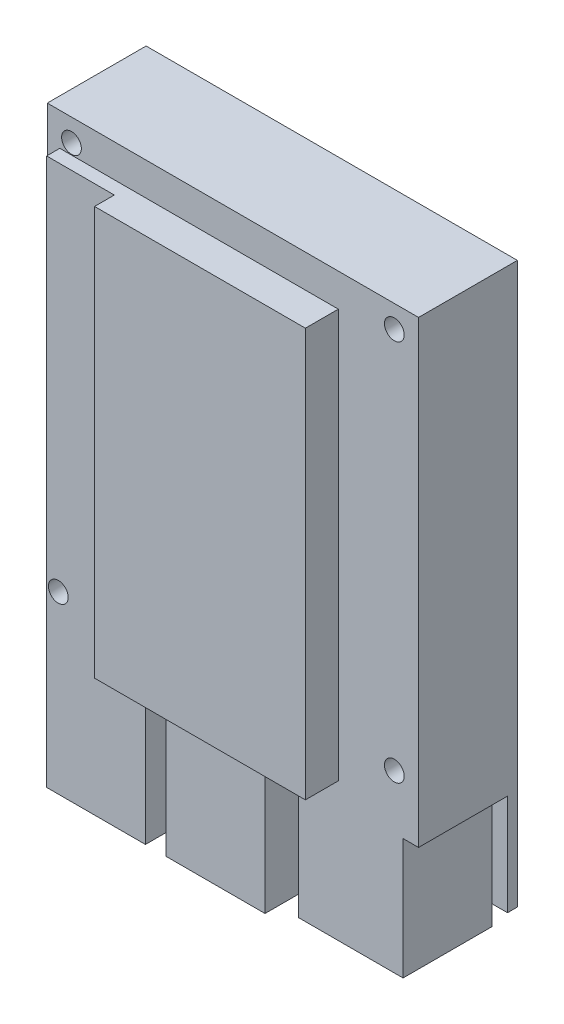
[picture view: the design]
ISO-10303-21;
HEADER;
FILE_DESCRIPTION(('STEP AP214'),'2;1');
FILE_NAME('part.step','',(''),(''),'','','');
FILE_SCHEMA(('AUTOMOTIVE_DESIGN { 1 0 10303 214 1 1 1 1 }'));
ENDSEC;
DATA;
#1=APPLICATION_CONTEXT('core data for automotive mechanical design processes');
#2=APPLICATION_PROTOCOL_DEFINITION('international standard','automotive_design',2000,#1);
#3=PRODUCT_CONTEXT('',#1,'mechanical');
#4=PRODUCT('Part','Part','',(#3));
#5=PRODUCT_RELATED_PRODUCT_CATEGORY('part','',(#4));
#6=PRODUCT_DEFINITION_FORMATION('','',#4);
#7=PRODUCT_DEFINITION_CONTEXT('part definition',#1,'design');
#8=PRODUCT_DEFINITION('design','',#6,#7);
#9=PRODUCT_DEFINITION_SHAPE('','',#8);
#10=(LENGTH_UNIT() NAMED_UNIT(*) SI_UNIT(.MILLI.,.METRE.));
#11=(NAMED_UNIT(*) PLANE_ANGLE_UNIT() SI_UNIT($,.RADIAN.));
#12=(NAMED_UNIT(*) SI_UNIT($,.STERADIAN.) SOLID_ANGLE_UNIT());
#13=UNCERTAINTY_MEASURE_WITH_UNIT(LENGTH_MEASURE(1.E-05),#10,'distance_accuracy_value','');
#14=(GEOMETRIC_REPRESENTATION_CONTEXT(3) GLOBAL_UNCERTAINTY_ASSIGNED_CONTEXT((#13)) GLOBAL_UNIT_ASSIGNED_CONTEXT((#10,
#11,#12)) REPRESENTATION_CONTEXT('',''));
#15=CARTESIAN_POINT('',(0.,0.,0.));
#16=DIRECTION('',(0.,0.,1.));
#17=DIRECTION('',(1.,0.,0.));
#18=AXIS2_PLACEMENT_3D('',#15,#16,#17);
#19=CARTESIAN_POINT('',(0.,85.,55.5));
#20=DIRECTION('',(0.,-1.,0.));
#21=DIRECTION('',(0.,0.,-1.));
#22=AXIS2_PLACEMENT_3D('',#19,#20,#21);
#23=PLANE('',#22);
#24=DIRECTION('',(0.,0.,-1.));
#25=VECTOR('',#24,1.);
#26=CARTESIAN_POINT('',(0.,85.,55.5));
#27=LINE('',#26,#25);
#28=CARTESIAN_POINT('',(0.,85.,50.5));
#29=VERTEX_POINT('',#28);
#30=CARTESIAN_POINT('',(0.,85.,35.5));
#31=VERTEX_POINT('',#30);
#32=EDGE_CURVE('E562',#29,#31,#27,.T.);
#33=ORIENTED_EDGE('',*,*,#32,.F.);
#34=DIRECTION('',(1.,0.,0.));
#35=VECTOR('',#34,1.);
#36=CARTESIAN_POINT('',(0.,85.,50.5));
#37=LINE('',#36,#35);
#38=CARTESIAN_POINT('',(56.35,85.,50.5));
#39=VERTEX_POINT('',#38);
#40=EDGE_CURVE('E549',#29,#39,#37,.T.);
#41=ORIENTED_EDGE('',*,*,#40,.T.);
#42=DIRECTION('',(0.,0.,-1.));
#43=VECTOR('',#42,1.);
#44=CARTESIAN_POINT('',(56.35,85.,55.5));
#45=LINE('',#44,#43);
#46=CARTESIAN_POINT('',(56.35,85.,35.5));
#47=VERTEX_POINT('',#46);
#48=EDGE_CURVE('E589',#39,#47,#45,.T.);
#49=ORIENTED_EDGE('',*,*,#48,.T.);
#50=DIRECTION('',(-1.,0.,0.));
#51=VECTOR('',#50,1.);
#52=CARTESIAN_POINT('',(-13.2262060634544,85.,35.5));
#53=LINE('',#52,#51);
#54=EDGE_CURVE('E374',#47,#31,#53,.T.);
#55=ORIENTED_EDGE('',*,*,#54,.T.);
#56=EDGE_LOOP('',(#33,#41,#49,#55));
#57=FACE_BOUND('',#56,.T.);
#58=ADVANCED_FACE('F58',(#57),#23,.F.);
#59=CARTESIAN_POINT('',(3.675,81.6,55.5));
#60=DIRECTION('',(0.,0.,-1.));
#61=DIRECTION('',(-1.,0.,0.));
#62=AXIS2_PLACEMENT_3D('',#59,#60,#61);
#63=CYLINDRICAL_SURFACE('',#62,1.5);
#64=CARTESIAN_POINT('',(3.675,81.6,35.5));
#65=DIRECTION('',(0.,0.,-1.));
#66=DIRECTION('',(-1.,0.,0.));
#67=AXIS2_PLACEMENT_3D('',#64,#65,#66);
#68=CIRCLE('',#67,1.5);
#69=CARTESIAN_POINT('',(2.175,81.6,35.5));
#70=VERTEX_POINT('',#69);
#71=EDGE_CURVE('E690',#70,#70,#68,.T.);
#72=ORIENTED_EDGE('',*,*,#71,.T.);
#73=EDGE_LOOP('',(#72));
#74=FACE_BOUND('',#73,.T.);
#75=CARTESIAN_POINT('',(3.675,81.6,50.5));
#76=DIRECTION('',(0.,0.,1.));
#77=DIRECTION('',(1.,0.,0.));
#78=AXIS2_PLACEMENT_3D('',#75,#76,#77);
#79=CIRCLE('',#78,1.5);
#80=CARTESIAN_POINT('',(5.175,81.6,50.5));
#81=VERTEX_POINT('',#80);
#82=EDGE_CURVE('E62',#81,#81,#79,.F.);
#83=ORIENTED_EDGE('',*,*,#82,.F.);
#84=EDGE_LOOP('',(#83));
#85=FACE_BOUND('',#84,.T.);
#86=ADVANCED_FACE('F803',(#74,#85),#63,.F.);
#87=CARTESIAN_POINT('',(0.,0.,55.5));
#88=DIRECTION('',(1.,0.,0.));
#89=DIRECTION('',(0.,0.,-1.));
#90=AXIS2_PLACEMENT_3D('',#87,#88,#89);
#91=PLANE('',#90);
#92=DIRECTION('',(0.,-1.,0.));
#93=VECTOR('',#92,1.);
#94=CARTESIAN_POINT('',(0.,85.,37.));
#95=LINE('',#94,#93);
#96=CARTESIAN_POINT('',(0.,15.3340933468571,37.));
#97=VERTEX_POINT('',#96);
#98=CARTESIAN_POINT('',(0.,0.,37.));
#99=VERTEX_POINT('',#98);
#100=EDGE_CURVE('E583',#97,#99,#95,.T.);
#101=ORIENTED_EDGE('',*,*,#100,.F.);
#102=DIRECTION('',(0.,0.,1.));
#103=VECTOR('',#102,1.);
#104=CARTESIAN_POINT('',(0.,15.3340933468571,-52.6027959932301));
#105=LINE('',#104,#103);
#106=CARTESIAN_POINT('',(0.,15.3340933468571,50.5));
#107=VERTEX_POINT('',#106);
#108=EDGE_CURVE('E660',#97,#107,#105,.T.);
#109=ORIENTED_EDGE('',*,*,#108,.T.);
#110=DIRECTION('',(0.,-1.,0.));
#111=VECTOR('',#110,1.);
#112=CARTESIAN_POINT('',(0.,85.,50.5));
#113=LINE('',#112,#111);
#114=EDGE_CURVE('E644',#29,#107,#113,.T.);
#115=ORIENTED_EDGE('',*,*,#114,.F.);
#116=ORIENTED_EDGE('',*,*,#32,.T.);
#117=DIRECTION('',(0.,-1.,0.));
#118=VECTOR('',#117,1.);
#119=CARTESIAN_POINT('',(0.,0.,35.5));
#120=LINE('',#119,#118);
#121=CARTESIAN_POINT('',(0.,0.,35.5));
#122=VERTEX_POINT('',#121);
#123=EDGE_CURVE('E384',#31,#122,#120,.T.);
#124=ORIENTED_EDGE('',*,*,#123,.T.);
#125=DIRECTION('',(0.,0.,-1.));
#126=VECTOR('',#125,1.);
#127=CARTESIAN_POINT('',(0.,0.,55.5));
#128=LINE('',#127,#126);
#129=EDGE_CURVE('E597',#99,#122,#128,.T.);
#130=ORIENTED_EDGE('',*,*,#129,.F.);
#131=EDGE_LOOP('',(#101,#109,#115,#116,#124,#130));
#132=FACE_BOUND('',#131,.T.);
#133=DIRECTION('',(0.,0.,1.));
#134=VECTOR('',#133,1.);
#135=CARTESIAN_POINT('',(0.,27.2,37.));
#136=LINE('',#135,#134);
#137=CARTESIAN_POINT('',(0.,27.2,37.));
#138=VERTEX_POINT('',#137);
#139=CARTESIAN_POINT('',(0.,27.2,43.5));
#140=VERTEX_POINT('',#139);
#141=EDGE_CURVE('E668',#138,#140,#136,.T.);
#142=ORIENTED_EDGE('',*,*,#141,.F.);
#143=CARTESIAN_POINT('',(0.,79.7,37.));
#144=VERTEX_POINT('',#143);
#145=EDGE_CURVE('E582',#144,#138,#95,.T.);
#146=ORIENTED_EDGE('',*,*,#145,.F.);
#147=DIRECTION('',(0.,0.,-1.));
#148=VECTOR('',#147,1.);
#149=CARTESIAN_POINT('',(0.,79.7,37.));
#150=LINE('',#149,#148);
#151=CARTESIAN_POINT('',(0.,79.7,43.5));
#152=VERTEX_POINT('',#151);
#153=EDGE_CURVE('E600',#152,#144,#150,.T.);
#154=ORIENTED_EDGE('',*,*,#153,.F.);
#155=DIRECTION('',(0.,1.,0.));
#156=VECTOR('',#155,1.);
#157=CARTESIAN_POINT('',(0.,79.7,43.5));
#158=LINE('',#157,#156);
#159=EDGE_CURVE('E664',#140,#152,#158,.T.);
#160=ORIENTED_EDGE('',*,*,#159,.F.);
#161=EDGE_LOOP('',(#142,#146,#154,#160));
#162=FACE_BOUND('',#161,.T.);
#163=ADVANCED_FACE('F60',(#132,#162),#91,.F.);
#164=CARTESIAN_POINT('',(1.90000000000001,85.,0.));
#165=DIRECTION('',(-1.,0.,0.));
#166=DIRECTION('',(0.,0.,1.));
#167=AXIS2_PLACEMENT_3D('',#164,#165,#166);
#168=PLANE('',#167);
#169=DIRECTION('',(0.,0.,1.));
#170=VECTOR('',#169,1.);
#171=CARTESIAN_POINT('',(1.90000000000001,80.,0.));
#172=LINE('',#171,#170);
#173=CARTESIAN_POINT('',(1.90000000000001,80.,50.5));
#174=VERTEX_POINT('',#173);
#175=CARTESIAN_POINT('',(1.90000000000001,80.,52.5));
#176=VERTEX_POINT('',#175);
#177=EDGE_CURVE('E77',#174,#176,#172,.T.);
#178=ORIENTED_EDGE('',*,*,#177,.F.);
#179=DIRECTION('',(0.,1.,0.));
#180=VECTOR('',#179,1.);
#181=CARTESIAN_POINT('',(1.90000000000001,85.,50.5));
#182=LINE('',#181,#180);
#183=CARTESIAN_POINT('',(1.90000000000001,15.3340933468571,50.5));
#184=VERTEX_POINT('',#183);
#185=EDGE_CURVE('E334',#184,#174,#182,.T.);
#186=ORIENTED_EDGE('',*,*,#185,.F.);
#187=DIRECTION('',(0.,0.,1.));
#188=VECTOR('',#187,1.);
#189=CARTESIAN_POINT('',(1.90000000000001,15.3340933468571,0.));
#190=LINE('',#189,#188);
#191=CARTESIAN_POINT('',(1.90000000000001,15.3340933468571,37.));
#192=VERTEX_POINT('',#191);
#193=EDGE_CURVE('E370',#192,#184,#190,.T.);
#194=ORIENTED_EDGE('',*,*,#193,.F.);
#195=DIRECTION('',(0.,-1.,0.));
#196=VECTOR('',#195,1.);
#197=CARTESIAN_POINT('',(1.90000000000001,85.,37.));
#198=LINE('',#197,#196);
#199=CARTESIAN_POINT('',(1.90000000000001,0.,37.));
#200=VERTEX_POINT('',#199);
#201=EDGE_CURVE('E580',#192,#200,#198,.T.);
#202=ORIENTED_EDGE('',*,*,#201,.T.);
#203=DIRECTION('',(0.,1.,0.));
#204=VECTOR('',#203,1.);
#205=CARTESIAN_POINT('',(1.90000000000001,-3.,37.));
#206=LINE('',#205,#204);
#207=CARTESIAN_POINT('',(1.90000000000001,-3.,37.));
#208=VERTEX_POINT('',#207);
#209=EDGE_CURVE('E427',#208,#200,#206,.T.);
#210=ORIENTED_EDGE('',*,*,#209,.F.);
#211=DIRECTION('',(0.,0.,-1.));
#212=VECTOR('',#211,1.);
#213=CARTESIAN_POINT('',(1.90000000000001,-3.,0.));
#214=LINE('',#213,#212);
#215=CARTESIAN_POINT('',(1.90000000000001,-3.,52.5));
#216=VERTEX_POINT('',#215);
#217=EDGE_CURVE('E424',#216,#208,#214,.T.);
#218=ORIENTED_EDGE('',*,*,#217,.F.);
#219=DIRECTION('',(0.,-1.,0.));
#220=VECTOR('',#219,1.);
#221=CARTESIAN_POINT('',(1.90000000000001,85.,52.5));
#222=LINE('',#221,#220);
#223=EDGE_CURVE('E336',#176,#216,#222,.T.);
#224=ORIENTED_EDGE('',*,*,#223,.F.);
#225=EDGE_LOOP('',(#178,#186,#194,#202,#210,#218,#224));
#226=FACE_BOUND('',#225,.T.);
#227=ADVANCED_FACE('F332',(#226),#168,.T.);
#228=CARTESIAN_POINT('',(0.,85.,37.));
#229=DIRECTION('',(0.,0.,-1.));
#230=DIRECTION('',(-1.,0.,0.));
#231=AXIS2_PLACEMENT_3D('',#228,#229,#230);
#232=PLANE('',#231);
#233=ORIENTED_EDGE('',*,*,#201,.F.);
#234=DIRECTION('',(1.,0.,0.));
#235=VECTOR('',#234,1.);
#236=CARTESIAN_POINT('',(0.,15.3340933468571,37.));
#237=LINE('',#236,#235);
#238=EDGE_CURVE('E652',#97,#192,#237,.T.);
#239=ORIENTED_EDGE('',*,*,#238,.F.);
#240=ORIENTED_EDGE('',*,*,#100,.T.);
#241=DIRECTION('',(1.,0.,0.));
#242=VECTOR('',#241,1.);
#243=CARTESIAN_POINT('',(0.,0.,37.));
#244=LINE('',#243,#242);
#245=EDGE_CURVE('E529',#99,#200,#244,.T.);
#246=ORIENTED_EDGE('',*,*,#245,.T.);
#247=EDGE_LOOP('',(#233,#239,#240,#246));
#248=FACE_BOUND('',#247,.T.);
#249=ADVANCED_FACE('F782',(#248),#232,.F.);
#250=CARTESIAN_POINT('',(0.,0.,55.5));
#251=DIRECTION('',(0.,1.,0.));
#252=DIRECTION('',(0.,0.,1.));
#253=AXIS2_PLACEMENT_3D('',#250,#251,#252);
#254=PLANE('',#253);
#255=ORIENTED_EDGE('',*,*,#129,.T.);
#256=DIRECTION('',(-1.,0.,0.));
#257=VECTOR('',#256,1.);
#258=CARTESIAN_POINT('',(-13.2262060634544,0.,35.5));
#259=LINE('',#258,#257);
#260=CARTESIAN_POINT('',(56.35,0.,35.5));
#261=VERTEX_POINT('',#260);
#262=EDGE_CURVE('E373',#261,#122,#259,.T.);
#263=ORIENTED_EDGE('',*,*,#262,.F.);
#264=DIRECTION('',(0.,0.,-1.));
#265=VECTOR('',#264,1.);
#266=CARTESIAN_POINT('',(56.35,0.,55.5));
#267=LINE('',#266,#265);
#268=CARTESIAN_POINT('',(56.35,0.,37.));
#269=VERTEX_POINT('',#268);
#270=EDGE_CURVE('E593',#269,#261,#267,.T.);
#271=ORIENTED_EDGE('',*,*,#270,.F.);
#272=DIRECTION('',(1.,0.,0.));
#273=VECTOR('',#272,1.);
#274=CARTESIAN_POINT('',(0.,0.,37.));
#275=LINE('',#274,#273);
#276=CARTESIAN_POINT('',(54.,0.,37.));
#277=VERTEX_POINT('',#276);
#278=EDGE_CURVE('E554',#277,#269,#275,.T.);
#279=ORIENTED_EDGE('',*,*,#278,.F.);
#280=DIRECTION('',(1.,0.,0.));
#281=VECTOR('',#280,1.);
#282=CARTESIAN_POINT('',(0.,0.,37.));
#283=LINE('',#282,#281);
#284=CARTESIAN_POINT('',(38.1,0.,37.));
#285=VERTEX_POINT('',#284);
#286=EDGE_CURVE('E412',#285,#277,#283,.T.);
#287=ORIENTED_EDGE('',*,*,#286,.F.);
#288=DIRECTION('',(1.,0.,0.));
#289=VECTOR('',#288,1.);
#290=CARTESIAN_POINT('',(0.,0.,37.));
#291=LINE('',#290,#289);
#292=CARTESIAN_POINT('',(35.05,0.,37.));
#293=VERTEX_POINT('',#292);
#294=EDGE_CURVE('E492',#293,#285,#291,.T.);
#295=ORIENTED_EDGE('',*,*,#294,.F.);
#296=DIRECTION('',(1.,0.,0.));
#297=VECTOR('',#296,1.);
#298=CARTESIAN_POINT('',(0.,0.,37.));
#299=LINE('',#298,#297);
#300=CARTESIAN_POINT('',(20.05,0.,37.));
#301=VERTEX_POINT('',#300);
#302=EDGE_CURVE('E442',#301,#293,#299,.T.);
#303=ORIENTED_EDGE('',*,*,#302,.F.);
#304=CARTESIAN_POINT('',(16.9,0.,37.));
#305=VERTEX_POINT('',#304);
#306=EDGE_CURVE('E436',#305,#301,#291,.T.);
#307=ORIENTED_EDGE('',*,*,#306,.F.);
#308=DIRECTION('',(1.,0.,0.));
#309=VECTOR('',#308,1.);
#310=CARTESIAN_POINT('',(0.,0.,37.));
#311=LINE('',#310,#309);
#312=EDGE_CURVE('E416',#200,#305,#311,.T.);
#313=ORIENTED_EDGE('',*,*,#312,.F.);
#314=ORIENTED_EDGE('',*,*,#245,.F.);
#315=EDGE_LOOP('',(#255,#263,#271,#279,#287,#295,#303,#307,#313,#314));
#316=FACE_BOUND('',#315,.T.);
#317=ADVANCED_FACE('F755',(#316),#254,.F.);
#318=CARTESIAN_POINT('',(0.,0.,55.5));
#319=DIRECTION('',(0.,0.,-1.));
#320=DIRECTION('',(-1.,0.,0.));
#321=AXIS2_PLACEMENT_3D('',#318,#319,#320);
#322=PLANE('',#321);
#323=DIRECTION('',(0.,-1.,0.));
#324=VECTOR('',#323,1.);
#325=CARTESIAN_POINT('',(44.175,85.,55.5));
#326=LINE('',#325,#324);
#327=CARTESIAN_POINT('',(44.175,80.,55.5));
#328=VERTEX_POINT('',#327);
#329=CARTESIAN_POINT('',(44.175,18.,55.5));
#330=VERTEX_POINT('',#329);
#331=EDGE_CURVE('E553',#328,#330,#326,.T.);
#332=ORIENTED_EDGE('',*,*,#331,.F.);
#333=DIRECTION('',(1.,0.,0.));
#334=VECTOR('',#333,1.);
#335=CARTESIAN_POINT('',(-13.2086276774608,80.,55.5));
#336=LINE('',#335,#334);
#337=CARTESIAN_POINT('',(12.175,80.,55.5));
#338=VERTEX_POINT('',#337);
#339=EDGE_CURVE('E327',#338,#328,#336,.T.);
#340=ORIENTED_EDGE('',*,*,#339,.F.);
#341=DIRECTION('',(0.,-1.,0.));
#342=VECTOR('',#341,1.);
#343=CARTESIAN_POINT('',(12.175,85.,55.5));
#344=LINE('',#343,#342);
#345=CARTESIAN_POINT('',(12.175,18.,55.5));
#346=VERTEX_POINT('',#345);
#347=EDGE_CURVE('E576',#338,#346,#344,.T.);
#348=ORIENTED_EDGE('',*,*,#347,.T.);
#349=DIRECTION('',(-1.,0.,0.));
#350=VECTOR('',#349,1.);
#351=CARTESIAN_POINT('',(0.,18.,55.5));
#352=LINE('',#351,#350);
#353=EDGE_CURVE('E491',#330,#346,#352,.T.);
#354=ORIENTED_EDGE('',*,*,#353,.F.);
#355=EDGE_LOOP('',(#332,#340,#348,#354));
#356=FACE_BOUND('',#355,.T.);
#357=ADVANCED_FACE('F717',(#356),#322,.F.);
#358=CARTESIAN_POINT('',(44.175,85.,0.));
#359=DIRECTION('',(-1.,0.,0.));
#360=DIRECTION('',(0.,0.,1.));
#361=AXIS2_PLACEMENT_3D('',#358,#359,#360);
#362=PLANE('',#361);
#363=DIRECTION('',(0.,-1.,0.));
#364=VECTOR('',#363,1.);
#365=CARTESIAN_POINT('',(44.175,85.,50.5));
#366=LINE('',#365,#364);
#367=CARTESIAN_POINT('',(44.175,80.,50.5));
#368=VERTEX_POINT('',#367);
#369=CARTESIAN_POINT('',(44.175,18.,50.5));
#370=VERTEX_POINT('',#369);
#371=EDGE_CURVE('E569',#368,#370,#366,.T.);
#372=ORIENTED_EDGE('',*,*,#371,.F.);
#373=DIRECTION('',(0.,0.,1.));
#374=VECTOR('',#373,1.);
#375=CARTESIAN_POINT('',(44.175,80.,0.));
#376=LINE('',#375,#374);
#377=EDGE_CURVE('E322',#368,#328,#376,.T.);
#378=ORIENTED_EDGE('',*,*,#377,.T.);
#379=ORIENTED_EDGE('',*,*,#331,.T.);
#380=DIRECTION('',(0.,0.,-1.));
#381=VECTOR('',#380,1.);
#382=CARTESIAN_POINT('',(44.175,18.,0.));
#383=LINE('',#382,#381);
#384=EDGE_CURVE('E487',#330,#370,#383,.T.);
#385=ORIENTED_EDGE('',*,*,#384,.T.);
#386=EDGE_LOOP('',(#372,#378,#379,#385));
#387=FACE_BOUND('',#386,.T.);
#388=ADVANCED_FACE('F715',(#387),#362,.F.);
#389=CARTESIAN_POINT('',(12.175,85.,0.));
#390=DIRECTION('',(-1.,0.,0.));
#391=DIRECTION('',(0.,0.,1.));
#392=AXIS2_PLACEMENT_3D('',#389,#390,#391);
#393=PLANE('',#392);
#394=DIRECTION('',(0.,0.,1.));
#395=VECTOR('',#394,1.);
#396=CARTESIAN_POINT('',(12.175,80.,0.));
#397=LINE('',#396,#395);
#398=CARTESIAN_POINT('',(12.175,80.,52.5));
#399=VERTEX_POINT('',#398);
#400=EDGE_CURVE('E338',#399,#338,#397,.T.);
#401=ORIENTED_EDGE('',*,*,#400,.F.);
#402=DIRECTION('',(0.,-1.,0.));
#403=VECTOR('',#402,1.);
#404=CARTESIAN_POINT('',(12.175,85.,52.5));
#405=LINE('',#404,#403);
#406=CARTESIAN_POINT('',(12.175,18.,52.5));
#407=VERTEX_POINT('',#406);
#408=EDGE_CURVE('E558',#399,#407,#405,.T.);
#409=ORIENTED_EDGE('',*,*,#408,.T.);
#410=DIRECTION('',(0.,0.,-1.));
#411=VECTOR('',#410,1.);
#412=CARTESIAN_POINT('',(12.175,18.,0.));
#413=LINE('',#412,#411);
#414=EDGE_CURVE('E496',#346,#407,#413,.T.);
#415=ORIENTED_EDGE('',*,*,#414,.F.);
#416=ORIENTED_EDGE('',*,*,#347,.F.);
#417=EDGE_LOOP('',(#401,#409,#415,#416));
#418=FACE_BOUND('',#417,.T.);
#419=ADVANCED_FACE('F721',(#418),#393,.T.);
#420=CARTESIAN_POINT('',(56.35,0.,55.5));
#421=DIRECTION('',(-1.,0.,0.));
#422=DIRECTION('',(0.,0.,1.));
#423=AXIS2_PLACEMENT_3D('',#420,#421,#422);
#424=PLANE('',#423);
#425=ORIENTED_EDGE('',*,*,#270,.T.);
#426=DIRECTION('',(0.,1.,0.));
#427=VECTOR('',#426,1.);
#428=CARTESIAN_POINT('',(56.35,0.,35.5));
#429=LINE('',#428,#427);
#430=EDGE_CURVE('E378',#261,#47,#429,.T.);
#431=ORIENTED_EDGE('',*,*,#430,.T.);
#432=ORIENTED_EDGE('',*,*,#48,.F.);
#433=DIRECTION('',(0.,1.,0.));
#434=VECTOR('',#433,1.);
#435=CARTESIAN_POINT('',(56.35,85.,50.5));
#436=LINE('',#435,#434);
#437=CARTESIAN_POINT('',(56.35,15.3340933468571,50.5));
#438=VERTEX_POINT('',#437);
#439=EDGE_CURVE('E647',#438,#39,#436,.T.);
#440=ORIENTED_EDGE('',*,*,#439,.F.);
#441=DIRECTION('',(0.,0.,1.));
#442=VECTOR('',#441,1.);
#443=CARTESIAN_POINT('',(56.35,15.3340933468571,-52.6027959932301));
#444=LINE('',#443,#442);
#445=CARTESIAN_POINT('',(56.35,15.3340933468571,37.));
#446=VERTEX_POINT('',#445);
#447=EDGE_CURVE('E654',#446,#438,#444,.T.);
#448=ORIENTED_EDGE('',*,*,#447,.F.);
#449=DIRECTION('',(0.,-1.,0.));
#450=VECTOR('',#449,1.);
#451=CARTESIAN_POINT('',(56.35,85.,37.));
#452=LINE('',#451,#450);
#453=EDGE_CURVE('E559',#446,#269,#452,.T.);
#454=ORIENTED_EDGE('',*,*,#453,.T.);
#455=EDGE_LOOP('',(#425,#431,#432,#440,#448,#454));
#456=FACE_BOUND('',#455,.T.);
#457=ADVANCED_FACE('F769',(#456),#424,.F.);
#458=CARTESIAN_POINT('',(0.,85.,37.));
#459=DIRECTION('',(0.,0.,-1.));
#460=DIRECTION('',(-1.,0.,0.));
#461=AXIS2_PLACEMENT_3D('',#458,#459,#460);
#462=PLANE('',#461);
#463=ORIENTED_EDGE('',*,*,#453,.F.);
#464=CARTESIAN_POINT('',(54.,15.3340933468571,37.));
#465=VERTEX_POINT('',#464);
#466=EDGE_CURVE('E656',#465,#446,#237,.T.);
#467=ORIENTED_EDGE('',*,*,#466,.F.);
#468=DIRECTION('',(0.,-1.,0.));
#469=VECTOR('',#468,1.);
#470=CARTESIAN_POINT('',(54.,85.,37.));
#471=LINE('',#470,#469);
#472=EDGE_CURVE('E563',#465,#277,#471,.T.);
#473=ORIENTED_EDGE('',*,*,#472,.T.);
#474=ORIENTED_EDGE('',*,*,#278,.T.);
#475=EDGE_LOOP('',(#463,#467,#473,#474));
#476=FACE_BOUND('',#475,.T.);
#477=ADVANCED_FACE('F814',(#476),#462,.F.);
#478=CARTESIAN_POINT('',(54.,85.,0.));
#479=DIRECTION('',(-1.,0.,0.));
#480=DIRECTION('',(0.,0.,1.));
#481=AXIS2_PLACEMENT_3D('',#478,#479,#480);
#482=PLANE('',#481);
#483=ORIENTED_EDGE('',*,*,#472,.F.);
#484=DIRECTION('',(0.,0.,1.));
#485=VECTOR('',#484,1.);
#486=CARTESIAN_POINT('',(54.,15.3340933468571,0.));
#487=LINE('',#486,#485);
#488=CARTESIAN_POINT('',(54.,15.3340933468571,50.5));
#489=VERTEX_POINT('',#488);
#490=EDGE_CURVE('E366',#465,#489,#487,.T.);
#491=ORIENTED_EDGE('',*,*,#490,.T.);
#492=DIRECTION('',(0.,-1.,0.));
#493=VECTOR('',#492,1.);
#494=CARTESIAN_POINT('',(54.,85.,50.5));
#495=LINE('',#494,#493);
#496=CARTESIAN_POINT('',(54.,-3.,50.5));
#497=VERTEX_POINT('',#496);
#498=EDGE_CURVE('E566',#489,#497,#495,.T.);
#499=ORIENTED_EDGE('',*,*,#498,.T.);
#500=DIRECTION('',(0.,0.,-1.));
#501=VECTOR('',#500,1.);
#502=CARTESIAN_POINT('',(54.,-3.,0.));
#503=LINE('',#502,#501);
#504=CARTESIAN_POINT('',(54.,-3.,37.));
#505=VERTEX_POINT('',#504);
#506=EDGE_CURVE('E466',#497,#505,#503,.T.);
#507=ORIENTED_EDGE('',*,*,#506,.T.);
#508=DIRECTION('',(0.,1.,0.));
#509=VECTOR('',#508,1.);
#510=CARTESIAN_POINT('',(54.,-3.,37.));
#511=LINE('',#510,#509);
#512=EDGE_CURVE('E456',#505,#277,#511,.T.);
#513=ORIENTED_EDGE('',*,*,#512,.T.);
#514=EDGE_LOOP('',(#483,#491,#499,#507,#513));
#515=FACE_BOUND('',#514,.T.);
#516=ADVANCED_FACE('F845',(#515),#482,.F.);
#517=CARTESIAN_POINT('',(0.,85.,50.5));
#518=DIRECTION('',(0.,0.,-1.));
#519=DIRECTION('',(-1.,0.,0.));
#520=AXIS2_PLACEMENT_3D('',#517,#518,#519);
#521=PLANE('',#520);
#522=CARTESIAN_POINT('',(52.675,23.6,50.5));
#523=DIRECTION('',(0.,0.,-1.));
#524=DIRECTION('',(-1.,0.,0.));
#525=AXIS2_PLACEMENT_3D('',#522,#523,#524);
#526=CIRCLE('',#525,1.5);
#527=CARTESIAN_POINT('',(51.175,23.6,50.5));
#528=VERTEX_POINT('',#527);
#529=EDGE_CURVE('E651',#528,#528,#526,.T.);
#530=ORIENTED_EDGE('',*,*,#529,.T.);
#531=EDGE_LOOP('',(#530));
#532=FACE_BOUND('',#531,.T.);
#533=ORIENTED_EDGE('',*,*,#439,.T.);
#534=ORIENTED_EDGE('',*,*,#40,.F.);
#535=ORIENTED_EDGE('',*,*,#114,.T.);
#536=DIRECTION('',(1.,0.,0.));
#537=VECTOR('',#536,1.);
#538=CARTESIAN_POINT('',(0.,15.3340933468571,50.5));
#539=LINE('',#538,#537);
#540=EDGE_CURVE('E344',#107,#184,#539,.T.);
#541=ORIENTED_EDGE('',*,*,#540,.T.);
#542=ORIENTED_EDGE('',*,*,#185,.T.);
#543=DIRECTION('',(1.,0.,0.));
#544=VECTOR('',#543,1.);
#545=CARTESIAN_POINT('',(-13.2086276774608,80.,50.5));
#546=LINE('',#545,#544);
#547=EDGE_CURVE('E319',#174,#368,#546,.T.);
#548=ORIENTED_EDGE('',*,*,#547,.T.);
#549=ORIENTED_EDGE('',*,*,#371,.T.);
#550=DIRECTION('',(1.,0.,0.));
#551=VECTOR('',#550,1.);
#552=CARTESIAN_POINT('',(0.,18.,50.5));
#553=LINE('',#552,#551);
#554=CARTESIAN_POINT('',(35.05,18.,50.5));
#555=VERTEX_POINT('',#554);
#556=EDGE_CURVE('E519',#555,#370,#553,.T.);
#557=ORIENTED_EDGE('',*,*,#556,.F.);
#558=DIRECTION('',(0.,1.,0.));
#559=VECTOR('',#558,1.);
#560=CARTESIAN_POINT('',(35.05,18.,50.5));
#561=LINE('',#560,#559);
#562=CARTESIAN_POINT('',(35.05,15.3340933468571,50.5));
#563=VERTEX_POINT('',#562);
#564=EDGE_CURVE('E347',#563,#555,#561,.T.);
#565=ORIENTED_EDGE('',*,*,#564,.F.);
#566=CARTESIAN_POINT('',(38.1,15.3340933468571,50.5));
#567=VERTEX_POINT('',#566);
#568=EDGE_CURVE('E634',#563,#567,#539,.T.);
#569=ORIENTED_EDGE('',*,*,#568,.T.);
#570=DIRECTION('',(0.,-1.,0.));
#571=VECTOR('',#570,1.);
#572=CARTESIAN_POINT('',(38.1,18.,50.5));
#573=LINE('',#572,#571);
#574=CARTESIAN_POINT('',(38.1,-3.,50.5));
#575=VERTEX_POINT('',#574);
#576=EDGE_CURVE('E88',#567,#575,#573,.T.);
#577=ORIENTED_EDGE('',*,*,#576,.T.);
#578=DIRECTION('',(1.,0.,0.));
#579=VECTOR('',#578,1.);
#580=CARTESIAN_POINT('',(0.,-3.,50.5));
#581=LINE('',#580,#579);
#582=EDGE_CURVE('E470',#575,#497,#581,.T.);
#583=ORIENTED_EDGE('',*,*,#582,.T.);
#584=ORIENTED_EDGE('',*,*,#498,.F.);
#585=EDGE_CURVE('E640',#489,#438,#539,.T.);
#586=ORIENTED_EDGE('',*,*,#585,.T.);
#587=EDGE_LOOP('',(#533,#534,#535,#541,#542,#548,#549,#557,#565,#569,#577,#583,#584,#586));
#588=FACE_BOUND('',#587,.T.);
#589=CARTESIAN_POINT('',(52.675,81.6,50.5));
#590=DIRECTION('',(0.,0.,-1.));
#591=DIRECTION('',(-1.,0.,0.));
#592=AXIS2_PLACEMENT_3D('',#589,#590,#591);
#593=CIRCLE('',#592,1.5);
#594=CARTESIAN_POINT('',(51.175,81.6,50.5));
#595=VERTEX_POINT('',#594);
#596=EDGE_CURVE('E676',#595,#595,#593,.T.);
#597=ORIENTED_EDGE('',*,*,#596,.T.);
#598=EDGE_LOOP('',(#597));
#599=FACE_BOUND('',#598,.T.);
#600=ORIENTED_EDGE('',*,*,#82,.T.);
#601=EDGE_LOOP('',(#600));
#602=FACE_BOUND('',#601,.T.);
#603=ADVANCED_FACE('F341',(#532,#588,#599,#602),#521,.F.);
#604=CARTESIAN_POINT('',(0.,85.,52.5));
#605=DIRECTION('',(0.,0.,-1.));
#606=DIRECTION('',(-1.,0.,0.));
#607=AXIS2_PLACEMENT_3D('',#604,#605,#606);
#608=PLANE('',#607);
#609=CARTESIAN_POINT('',(3.67500000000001,23.6,52.5));
#610=DIRECTION('',(0.,0.,-1.));
#611=DIRECTION('',(-1.,0.,0.));
#612=AXIS2_PLACEMENT_3D('',#609,#610,#611);
#613=CIRCLE('',#612,1.5);
#614=CARTESIAN_POINT('',(2.17500000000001,23.6,52.5));
#615=VERTEX_POINT('',#614);
#616=EDGE_CURVE('E674',#615,#615,#613,.T.);
#617=ORIENTED_EDGE('',*,*,#616,.T.);
#618=EDGE_LOOP('',(#617));
#619=FACE_BOUND('',#618,.T.);
#620=ORIENTED_EDGE('',*,*,#408,.F.);
#621=DIRECTION('',(-1.,0.,0.));
#622=VECTOR('',#621,1.);
#623=CARTESIAN_POINT('',(0.,80.,52.5));
#624=LINE('',#623,#622);
#625=EDGE_CURVE('E704',#399,#176,#624,.T.);
#626=ORIENTED_EDGE('',*,*,#625,.T.);
#627=ORIENTED_EDGE('',*,*,#223,.T.);
#628=DIRECTION('',(1.,0.,0.));
#629=VECTOR('',#628,1.);
#630=CARTESIAN_POINT('',(0.,-3.,52.5));
#631=LINE('',#630,#629);
#632=CARTESIAN_POINT('',(16.9,-3.,52.5));
#633=VERTEX_POINT('',#632);
#634=EDGE_CURVE('E420',#216,#633,#631,.T.);
#635=ORIENTED_EDGE('',*,*,#634,.T.);
#636=DIRECTION('',(0.,-1.,0.));
#637=VECTOR('',#636,1.);
#638=CARTESIAN_POINT('',(16.9,18.,52.5));
#639=LINE('',#638,#637);
#640=CARTESIAN_POINT('',(16.9,18.,52.5));
#641=VERTEX_POINT('',#640);
#642=EDGE_CURVE('E523',#641,#633,#639,.T.);
#643=ORIENTED_EDGE('',*,*,#642,.F.);
#644=DIRECTION('',(1.,0.,0.));
#645=VECTOR('',#644,1.);
#646=CARTESIAN_POINT('',(0.,18.,52.5));
#647=LINE('',#646,#645);
#648=EDGE_CURVE('E500',#407,#641,#647,.T.);
#649=ORIENTED_EDGE('',*,*,#648,.F.);
#650=EDGE_LOOP('',(#620,#626,#627,#635,#643,#649));
#651=FACE_BOUND('',#650,.T.);
#652=ADVANCED_FACE('F724',(#619,#651),#608,.F.);
#653=CARTESIAN_POINT('',(38.1,18.,0.));
#654=DIRECTION('',(-1.,0.,0.));
#655=DIRECTION('',(0.,0.,1.));
#656=AXIS2_PLACEMENT_3D('',#653,#654,#655);
#657=PLANE('',#656);
#658=DIRECTION('',(0.,0.,1.));
#659=VECTOR('',#658,1.);
#660=CARTESIAN_POINT('',(38.1,15.3340933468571,0.));
#661=LINE('',#660,#659);
#662=CARTESIAN_POINT('',(38.1,15.3340933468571,37.));
#663=VERTEX_POINT('',#662);
#664=EDGE_CURVE('E363',#663,#567,#661,.T.);
#665=ORIENTED_EDGE('',*,*,#664,.F.);
#666=DIRECTION('',(0.,-1.,0.));
#667=VECTOR('',#666,1.);
#668=CARTESIAN_POINT('',(38.1,18.,37.));
#669=LINE('',#668,#667);
#670=EDGE_CURVE('E530',#663,#285,#669,.T.);
#671=ORIENTED_EDGE('',*,*,#670,.T.);
#672=DIRECTION('',(0.,1.,0.));
#673=VECTOR('',#672,1.);
#674=CARTESIAN_POINT('',(38.1,-3.,37.));
#675=LINE('',#674,#673);
#676=CARTESIAN_POINT('',(38.1,-3.,37.));
#677=VERTEX_POINT('',#676);
#678=EDGE_CURVE('E477',#677,#285,#675,.T.);
#679=ORIENTED_EDGE('',*,*,#678,.F.);
#680=DIRECTION('',(0.,0.,-1.));
#681=VECTOR('',#680,1.);
#682=CARTESIAN_POINT('',(38.1,-3.,0.));
#683=LINE('',#682,#681);
#684=EDGE_CURVE('E474',#575,#677,#683,.T.);
#685=ORIENTED_EDGE('',*,*,#684,.F.);
#686=ORIENTED_EDGE('',*,*,#576,.F.);
#687=EDGE_LOOP('',(#665,#671,#679,#685,#686));
#688=FACE_BOUND('',#687,.T.);
#689=ADVANCED_FACE('F839',(#688),#657,.T.);
#690=CARTESIAN_POINT('',(0.,18.,37.));
#691=DIRECTION('',(0.,0.,-1.));
#692=DIRECTION('',(-1.,0.,0.));
#693=AXIS2_PLACEMENT_3D('',#690,#691,#692);
#694=PLANE('',#693);
#695=ORIENTED_EDGE('',*,*,#670,.F.);
#696=CARTESIAN_POINT('',(35.05,15.3340933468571,37.));
#697=VERTEX_POINT('',#696);
#698=EDGE_CURVE('E753',#697,#663,#237,.T.);
#699=ORIENTED_EDGE('',*,*,#698,.F.);
#700=DIRECTION('',(0.,-1.,0.));
#701=VECTOR('',#700,1.);
#702=CARTESIAN_POINT('',(35.05,18.,37.));
#703=LINE('',#702,#701);
#704=EDGE_CURVE('E533',#697,#293,#703,.T.);
#705=ORIENTED_EDGE('',*,*,#704,.T.);
#706=ORIENTED_EDGE('',*,*,#294,.T.);
#707=EDGE_LOOP('',(#695,#699,#705,#706));
#708=FACE_BOUND('',#707,.T.);
#709=ADVANCED_FACE('F752',(#708),#694,.F.);
#710=CARTESIAN_POINT('',(35.05,18.,0.));
#711=DIRECTION('',(-1.,0.,0.));
#712=DIRECTION('',(0.,0.,1.));
#713=AXIS2_PLACEMENT_3D('',#710,#711,#712);
#714=PLANE('',#713);
#715=DIRECTION('',(0.,0.,1.));
#716=VECTOR('',#715,1.);
#717=CARTESIAN_POINT('',(35.05,15.3340933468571,0.));
#718=LINE('',#717,#716);
#719=EDGE_CURVE('E353',#697,#563,#718,.T.);
#720=ORIENTED_EDGE('',*,*,#719,.T.);
#721=ORIENTED_EDGE('',*,*,#564,.T.);
#722=DIRECTION('',(0.,0.,-1.));
#723=VECTOR('',#722,1.);
#724=CARTESIAN_POINT('',(35.05,18.,0.));
#725=LINE('',#724,#723);
#726=CARTESIAN_POINT('',(35.05,18.,52.5));
#727=VERTEX_POINT('',#726);
#728=EDGE_CURVE('E515',#727,#555,#725,.T.);
#729=ORIENTED_EDGE('',*,*,#728,.F.);
#730=DIRECTION('',(0.,-1.,0.));
#731=VECTOR('',#730,1.);
#732=CARTESIAN_POINT('',(35.05,18.,52.5));
#733=LINE('',#732,#731);
#734=CARTESIAN_POINT('',(35.05,-3.,52.5));
#735=VERTEX_POINT('',#734);
#736=EDGE_CURVE('E536',#727,#735,#733,.T.);
#737=ORIENTED_EDGE('',*,*,#736,.T.);
#738=DIRECTION('',(0.,0.,-1.));
#739=VECTOR('',#738,1.);
#740=CARTESIAN_POINT('',(35.05,-3.,0.));
#741=LINE('',#740,#739);
#742=CARTESIAN_POINT('',(35.05,-3.,37.));
#743=VERTEX_POINT('',#742);
#744=EDGE_CURVE('E437',#735,#743,#741,.T.);
#745=ORIENTED_EDGE('',*,*,#744,.T.);
#746=DIRECTION('',(0.,1.,0.));
#747=VECTOR('',#746,1.);
#748=CARTESIAN_POINT('',(35.05,-3.,37.));
#749=LINE('',#748,#747);
#750=EDGE_CURVE('E452',#743,#293,#749,.T.);
#751=ORIENTED_EDGE('',*,*,#750,.T.);
#752=ORIENTED_EDGE('',*,*,#704,.F.);
#753=EDGE_LOOP('',(#720,#721,#729,#737,#745,#751,#752));
#754=FACE_BOUND('',#753,.T.);
#755=ADVANCED_FACE('F629',(#754),#714,.F.);
#756=CARTESIAN_POINT('',(0.,18.,52.5));
#757=DIRECTION('',(0.,0.,-1.));
#758=DIRECTION('',(-1.,0.,0.));
#759=AXIS2_PLACEMENT_3D('',#756,#757,#758);
#760=PLANE('',#759);
#761=DIRECTION('',(0.,-1.,0.));
#762=VECTOR('',#761,1.);
#763=CARTESIAN_POINT('',(20.05,18.,52.5));
#764=LINE('',#763,#762);
#765=CARTESIAN_POINT('',(20.05,18.,52.5));
#766=VERTEX_POINT('',#765);
#767=CARTESIAN_POINT('',(20.05,-3.,52.5));
#768=VERTEX_POINT('',#767);
#769=EDGE_CURVE('E539',#766,#768,#764,.T.);
#770=ORIENTED_EDGE('',*,*,#769,.T.);
#771=DIRECTION('',(1.,0.,0.));
#772=VECTOR('',#771,1.);
#773=CARTESIAN_POINT('',(0.,-3.,52.5));
#774=LINE('',#773,#772);
#775=EDGE_CURVE('E441',#768,#735,#774,.T.);
#776=ORIENTED_EDGE('',*,*,#775,.T.);
#777=ORIENTED_EDGE('',*,*,#736,.F.);
#778=DIRECTION('',(1.,0.,0.));
#779=VECTOR('',#778,1.);
#780=CARTESIAN_POINT('',(0.,18.,52.5));
#781=LINE('',#780,#779);
#782=EDGE_CURVE('E511',#766,#727,#781,.T.);
#783=ORIENTED_EDGE('',*,*,#782,.F.);
#784=EDGE_LOOP('',(#770,#776,#777,#783));
#785=FACE_BOUND('',#784,.T.);
#786=ADVANCED_FACE('F624',(#785),#760,.F.);
#787=CARTESIAN_POINT('',(20.05,18.,0.));
#788=DIRECTION('',(-1.,0.,0.));
#789=DIRECTION('',(0.,0.,1.));
#790=AXIS2_PLACEMENT_3D('',#787,#788,#789);
#791=PLANE('',#790);
#792=DIRECTION('',(0.,1.,0.));
#793=VECTOR('',#792,1.);
#794=CARTESIAN_POINT('',(20.05,18.,50.5));
#795=LINE('',#794,#793);
#796=CARTESIAN_POINT('',(20.05,15.3340933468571,50.5));
#797=VERTEX_POINT('',#796);
#798=CARTESIAN_POINT('',(20.05,18.,50.5));
#799=VERTEX_POINT('',#798);
#800=EDGE_CURVE('E357',#797,#799,#795,.T.);
#801=ORIENTED_EDGE('',*,*,#800,.F.);
#802=DIRECTION('',(0.,0.,1.));
#803=VECTOR('',#802,1.);
#804=CARTESIAN_POINT('',(20.05,15.3340933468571,0.));
#805=LINE('',#804,#803);
#806=CARTESIAN_POINT('',(20.05,15.3340933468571,37.));
#807=VERTEX_POINT('',#806);
#808=EDGE_CURVE('E346',#807,#797,#805,.T.);
#809=ORIENTED_EDGE('',*,*,#808,.F.);
#810=DIRECTION('',(0.,-1.,0.));
#811=VECTOR('',#810,1.);
#812=CARTESIAN_POINT('',(20.05,18.,37.));
#813=LINE('',#812,#811);
#814=EDGE_CURVE('E542',#807,#301,#813,.T.);
#815=ORIENTED_EDGE('',*,*,#814,.T.);
#816=DIRECTION('',(0.,1.,0.));
#817=VECTOR('',#816,1.);
#818=CARTESIAN_POINT('',(20.05,-3.,37.));
#819=LINE('',#818,#817);
#820=CARTESIAN_POINT('',(20.05,-3.,37.));
#821=VERTEX_POINT('',#820);
#822=EDGE_CURVE('E430',#821,#301,#819,.T.);
#823=ORIENTED_EDGE('',*,*,#822,.F.);
#824=DIRECTION('',(0.,0.,-1.));
#825=VECTOR('',#824,1.);
#826=CARTESIAN_POINT('',(20.05,-3.,0.));
#827=LINE('',#826,#825);
#828=EDGE_CURVE('E446',#768,#821,#827,.T.);
#829=ORIENTED_EDGE('',*,*,#828,.F.);
#830=ORIENTED_EDGE('',*,*,#769,.F.);
#831=DIRECTION('',(0.,0.,-1.));
#832=VECTOR('',#831,1.);
#833=CARTESIAN_POINT('',(20.05,18.,0.));
#834=LINE('',#833,#832);
#835=EDGE_CURVE('E507',#766,#799,#834,.T.);
#836=ORIENTED_EDGE('',*,*,#835,.T.);
#837=EDGE_LOOP('',(#801,#809,#815,#823,#829,#830,#836));
#838=FACE_BOUND('',#837,.T.);
#839=ADVANCED_FACE('F619',(#838),#791,.T.);
#840=ORIENTED_EDGE('',*,*,#814,.F.);
#841=CARTESIAN_POINT('',(16.9,15.3340933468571,37.));
#842=VERTEX_POINT('',#841);
#843=EDGE_CURVE('E655',#842,#807,#237,.T.);
#844=ORIENTED_EDGE('',*,*,#843,.F.);
#845=DIRECTION('',(0.,-1.,0.));
#846=VECTOR('',#845,1.);
#847=CARTESIAN_POINT('',(16.9,18.,37.));
#848=LINE('',#847,#846);
#849=EDGE_CURVE('E545',#842,#305,#848,.T.);
#850=ORIENTED_EDGE('',*,*,#849,.T.);
#851=ORIENTED_EDGE('',*,*,#306,.T.);
#852=EDGE_LOOP('',(#840,#844,#850,#851));
#853=FACE_BOUND('',#852,.T.);
#854=ADVANCED_FACE('F737',(#853),#694,.F.);
#855=CARTESIAN_POINT('',(16.9,18.,0.));
#856=DIRECTION('',(-1.,0.,0.));
#857=DIRECTION('',(0.,0.,1.));
#858=AXIS2_PLACEMENT_3D('',#855,#856,#857);
#859=PLANE('',#858);
#860=DIRECTION('',(0.,0.,1.));
#861=VECTOR('',#860,1.);
#862=CARTESIAN_POINT('',(16.9,15.3340933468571,0.));
#863=LINE('',#862,#861);
#864=CARTESIAN_POINT('',(16.9,15.3340933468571,50.5));
#865=VERTEX_POINT('',#864);
#866=EDGE_CURVE('E12',#842,#865,#863,.T.);
#867=ORIENTED_EDGE('',*,*,#866,.T.);
#868=DIRECTION('',(0.,1.,0.));
#869=VECTOR('',#868,1.);
#870=CARTESIAN_POINT('',(16.9,18.,50.5));
#871=LINE('',#870,#869);
#872=CARTESIAN_POINT('',(16.9,18.,50.5));
#873=VERTEX_POINT('',#872);
#874=EDGE_CURVE('E611',#865,#873,#871,.T.);
#875=ORIENTED_EDGE('',*,*,#874,.T.);
#876=DIRECTION('',(0.,0.,-1.));
#877=VECTOR('',#876,1.);
#878=CARTESIAN_POINT('',(16.9,18.,0.));
#879=LINE('',#878,#877);
#880=EDGE_CURVE('E504',#641,#873,#879,.T.);
#881=ORIENTED_EDGE('',*,*,#880,.F.);
#882=ORIENTED_EDGE('',*,*,#642,.T.);
#883=DIRECTION('',(0.,0.,-1.));
#884=VECTOR('',#883,1.);
#885=CARTESIAN_POINT('',(16.9,-3.,0.));
#886=LINE('',#885,#884);
#887=CARTESIAN_POINT('',(16.9,-3.,37.));
#888=VERTEX_POINT('',#887);
#889=EDGE_CURVE('E415',#633,#888,#886,.T.);
#890=ORIENTED_EDGE('',*,*,#889,.T.);
#891=DIRECTION('',(0.,1.,0.));
#892=VECTOR('',#891,1.);
#893=CARTESIAN_POINT('',(16.9,-3.,37.));
#894=LINE('',#893,#892);
#895=EDGE_CURVE('E433',#888,#305,#894,.T.);
#896=ORIENTED_EDGE('',*,*,#895,.T.);
#897=ORIENTED_EDGE('',*,*,#849,.F.);
#898=EDGE_LOOP('',(#867,#875,#881,#882,#890,#896,#897));
#899=FACE_BOUND('',#898,.T.);
#900=ADVANCED_FACE('F728',(#899),#859,.F.);
#901=CARTESIAN_POINT('',(0.,18.,0.));
#902=DIRECTION('',(0.,-1.,0.));
#903=DIRECTION('',(0.,0.,-1.));
#904=AXIS2_PLACEMENT_3D('',#901,#902,#903);
#905=PLANE('',#904);
#906=ORIENTED_EDGE('',*,*,#728,.T.);
#907=ORIENTED_EDGE('',*,*,#556,.T.);
#908=ORIENTED_EDGE('',*,*,#384,.F.);
#909=ORIENTED_EDGE('',*,*,#353,.T.);
#910=ORIENTED_EDGE('',*,*,#414,.T.);
#911=ORIENTED_EDGE('',*,*,#648,.T.);
#912=ORIENTED_EDGE('',*,*,#880,.T.);
#913=DIRECTION('',(-1.,0.,0.));
#914=VECTOR('',#913,1.);
#915=CARTESIAN_POINT('',(0.,18.,50.5));
#916=LINE('',#915,#914);
#917=EDGE_CURVE('E68',#799,#873,#916,.T.);
#918=ORIENTED_EDGE('',*,*,#917,.F.);
#919=ORIENTED_EDGE('',*,*,#835,.F.);
#920=ORIENTED_EDGE('',*,*,#782,.T.);
#921=EDGE_LOOP('',(#906,#907,#908,#909,#910,#911,#912,#918,#919,#920));
#922=FACE_BOUND('',#921,.T.);
#923=ADVANCED_FACE('F615',(#922),#905,.T.);
#924=CARTESIAN_POINT('',(0.,-3.,37.));
#925=DIRECTION('',(0.,0.,1.));
#926=DIRECTION('',(1.,0.,0.));
#927=AXIS2_PLACEMENT_3D('',#924,#925,#926);
#928=PLANE('',#927);
#929=ORIENTED_EDGE('',*,*,#286,.T.);
#930=ORIENTED_EDGE('',*,*,#512,.F.);
#931=DIRECTION('',(1.,0.,0.));
#932=VECTOR('',#931,1.);
#933=CARTESIAN_POINT('',(0.,-3.,37.));
#934=LINE('',#933,#932);
#935=EDGE_CURVE('E463',#677,#505,#934,.T.);
#936=ORIENTED_EDGE('',*,*,#935,.F.);
#937=ORIENTED_EDGE('',*,*,#678,.T.);
#938=EDGE_LOOP('',(#929,#930,#936,#937));
#939=FACE_BOUND('',#938,.T.);
#940=ADVANCED_FACE('F924',(#939),#928,.F.);
#941=CARTESIAN_POINT('',(0.,-3.,0.));
#942=DIRECTION('',(0.,-1.,0.));
#943=DIRECTION('',(0.,0.,-1.));
#944=AXIS2_PLACEMENT_3D('',#941,#942,#943);
#945=PLANE('',#944);
#946=ORIENTED_EDGE('',*,*,#935,.T.);
#947=ORIENTED_EDGE('',*,*,#506,.F.);
#948=ORIENTED_EDGE('',*,*,#582,.F.);
#949=ORIENTED_EDGE('',*,*,#684,.T.);
#950=EDGE_LOOP('',(#946,#947,#948,#949));
#951=FACE_BOUND('',#950,.T.);
#952=ADVANCED_FACE('F920',(#951),#945,.T.);
#953=CARTESIAN_POINT('',(0.,-3.,37.));
#954=DIRECTION('',(0.,0.,1.));
#955=DIRECTION('',(1.,0.,0.));
#956=AXIS2_PLACEMENT_3D('',#953,#954,#955);
#957=PLANE('',#956);
#958=ORIENTED_EDGE('',*,*,#302,.T.);
#959=ORIENTED_EDGE('',*,*,#750,.F.);
#960=DIRECTION('',(1.,0.,0.));
#961=VECTOR('',#960,1.);
#962=CARTESIAN_POINT('',(0.,-3.,37.));
#963=LINE('',#962,#961);
#964=EDGE_CURVE('E449',#821,#743,#963,.T.);
#965=ORIENTED_EDGE('',*,*,#964,.F.);
#966=ORIENTED_EDGE('',*,*,#822,.T.);
#967=EDGE_LOOP('',(#958,#959,#965,#966));
#968=FACE_BOUND('',#967,.T.);
#969=ADVANCED_FACE('F743',(#968),#957,.F.);
#970=CARTESIAN_POINT('',(0.,-3.,0.));
#971=DIRECTION('',(0.,-1.,0.));
#972=DIRECTION('',(0.,0.,-1.));
#973=AXIS2_PLACEMENT_3D('',#970,#971,#972);
#974=PLANE('',#973);
#975=ORIENTED_EDGE('',*,*,#744,.F.);
#976=ORIENTED_EDGE('',*,*,#775,.F.);
#977=ORIENTED_EDGE('',*,*,#828,.T.);
#978=ORIENTED_EDGE('',*,*,#964,.T.);
#979=EDGE_LOOP('',(#975,#976,#977,#978));
#980=FACE_BOUND('',#979,.T.);
#981=ADVANCED_FACE('F747',(#980),#974,.T.);
#982=CARTESIAN_POINT('',(0.,-3.,37.));
#983=DIRECTION('',(0.,0.,1.));
#984=DIRECTION('',(1.,0.,0.));
#985=AXIS2_PLACEMENT_3D('',#982,#983,#984);
#986=PLANE('',#985);
#987=ORIENTED_EDGE('',*,*,#312,.T.);
#988=ORIENTED_EDGE('',*,*,#895,.F.);
#989=DIRECTION('',(1.,0.,0.));
#990=VECTOR('',#989,1.);
#991=CARTESIAN_POINT('',(0.,-3.,37.));
#992=LINE('',#991,#990);
#993=EDGE_CURVE('E413',#208,#888,#992,.T.);
#994=ORIENTED_EDGE('',*,*,#993,.F.);
#995=ORIENTED_EDGE('',*,*,#209,.T.);
#996=EDGE_LOOP('',(#987,#988,#994,#995));
#997=FACE_BOUND('',#996,.T.);
#998=ADVANCED_FACE('F786',(#997),#986,.F.);
#999=CARTESIAN_POINT('',(0.,-3.,0.));
#1000=DIRECTION('',(0.,-1.,0.));
#1001=DIRECTION('',(0.,0.,-1.));
#1002=AXIS2_PLACEMENT_3D('',#999,#1000,#1001);
#1003=PLANE('',#1002);
#1004=ORIENTED_EDGE('',*,*,#993,.T.);
#1005=ORIENTED_EDGE('',*,*,#889,.F.);
#1006=ORIENTED_EDGE('',*,*,#634,.F.);
#1007=ORIENTED_EDGE('',*,*,#217,.T.);
#1008=EDGE_LOOP('',(#1004,#1005,#1006,#1007));
#1009=FACE_BOUND('',#1008,.T.);
#1010=ADVANCED_FACE('F789',(#1009),#1003,.T.);
#1011=CARTESIAN_POINT('',(-0.499999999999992,79.7,37.));
#1012=DIRECTION('',(0.,0.,1.));
#1013=DIRECTION('',(0.,-1.,0.));
#1014=AXIS2_PLACEMENT_3D('',#1011,#1012,#1013);
#1015=PLANE('',#1014);
#1016=DIRECTION('',(1.,0.,0.));
#1017=VECTOR('',#1016,1.);
#1018=CARTESIAN_POINT('',(-0.499999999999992,79.7,37.));
#1019=LINE('',#1018,#1017);
#1020=CARTESIAN_POINT('',(-0.499999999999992,79.7,37.));
#1021=VERTEX_POINT('',#1020);
#1022=EDGE_CURVE('E399',#1021,#144,#1019,.T.);
#1023=ORIENTED_EDGE('',*,*,#1022,.T.);
#1024=ORIENTED_EDGE('',*,*,#145,.T.);
#1025=DIRECTION('',(1.,0.,0.));
#1026=VECTOR('',#1025,1.);
#1027=CARTESIAN_POINT('',(-0.499999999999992,27.2,37.));
#1028=LINE('',#1027,#1026);
#1029=CARTESIAN_POINT('',(-0.499999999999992,27.2,37.));
#1030=VERTEX_POINT('',#1029);
#1031=EDGE_CURVE('E409',#1030,#138,#1028,.T.);
#1032=ORIENTED_EDGE('',*,*,#1031,.F.);
#1033=DIRECTION('',(0.,-1.,0.));
#1034=VECTOR('',#1033,1.);
#1035=CARTESIAN_POINT('',(-0.499999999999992,79.7,37.));
#1036=LINE('',#1035,#1034);
#1037=EDGE_CURVE('E387',#1021,#1030,#1036,.T.);
#1038=ORIENTED_EDGE('',*,*,#1037,.F.);
#1039=EDGE_LOOP('',(#1023,#1024,#1032,#1038));
#1040=FACE_BOUND('',#1039,.T.);
#1041=ADVANCED_FACE('F791',(#1040),#1015,.F.);
#1042=CARTESIAN_POINT('',(-0.499999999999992,27.2,37.));
#1043=DIRECTION('',(0.,1.,0.));
#1044=DIRECTION('',(0.,0.,1.));
#1045=AXIS2_PLACEMENT_3D('',#1042,#1043,#1044);
#1046=PLANE('',#1045);
#1047=ORIENTED_EDGE('',*,*,#1031,.T.);
#1048=ORIENTED_EDGE('',*,*,#141,.T.);
#1049=DIRECTION('',(1.,0.,0.));
#1050=VECTOR('',#1049,1.);
#1051=CARTESIAN_POINT('',(-0.499999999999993,27.2,43.5));
#1052=LINE('',#1051,#1050);
#1053=CARTESIAN_POINT('',(-0.499999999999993,27.2,43.5));
#1054=VERTEX_POINT('',#1053);
#1055=EDGE_CURVE('E405',#1054,#140,#1052,.T.);
#1056=ORIENTED_EDGE('',*,*,#1055,.F.);
#1057=DIRECTION('',(0.,0.,1.));
#1058=VECTOR('',#1057,1.);
#1059=CARTESIAN_POINT('',(-0.499999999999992,27.2,37.));
#1060=LINE('',#1059,#1058);
#1061=EDGE_CURVE('E391',#1030,#1054,#1060,.T.);
#1062=ORIENTED_EDGE('',*,*,#1061,.F.);
#1063=EDGE_LOOP('',(#1047,#1048,#1056,#1062));
#1064=FACE_BOUND('',#1063,.T.);
#1065=ADVANCED_FACE('F797',(#1064),#1046,.F.);
#1066=CARTESIAN_POINT('',(-0.499999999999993,79.7,43.5));
#1067=DIRECTION('',(0.,0.,-1.));
#1068=DIRECTION('',(0.,1.,0.));
#1069=AXIS2_PLACEMENT_3D('',#1066,#1067,#1068);
#1070=PLANE('',#1069);
#1071=ORIENTED_EDGE('',*,*,#1055,.T.);
#1072=ORIENTED_EDGE('',*,*,#159,.T.);
#1073=DIRECTION('',(1.,0.,0.));
#1074=VECTOR('',#1073,1.);
#1075=CARTESIAN_POINT('',(-0.499999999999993,79.7,43.5));
#1076=LINE('',#1075,#1074);
#1077=CARTESIAN_POINT('',(-0.499999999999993,79.7,43.5));
#1078=VERTEX_POINT('',#1077);
#1079=EDGE_CURVE('E402',#1078,#152,#1076,.T.);
#1080=ORIENTED_EDGE('',*,*,#1079,.F.);
#1081=DIRECTION('',(0.,1.,0.));
#1082=VECTOR('',#1081,1.);
#1083=CARTESIAN_POINT('',(-0.499999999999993,79.7,43.5));
#1084=LINE('',#1083,#1082);
#1085=EDGE_CURVE('E394',#1054,#1078,#1084,.T.);
#1086=ORIENTED_EDGE('',*,*,#1085,.F.);
#1087=EDGE_LOOP('',(#1071,#1072,#1080,#1086));
#1088=FACE_BOUND('',#1087,.T.);
#1089=ADVANCED_FACE('F884',(#1088),#1070,.F.);
#1090=CARTESIAN_POINT('',(-0.499999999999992,79.7,37.));
#1091=DIRECTION('',(0.,-1.,0.));
#1092=DIRECTION('',(0.,0.,-1.));
#1093=AXIS2_PLACEMENT_3D('',#1090,#1091,#1092);
#1094=PLANE('',#1093);
#1095=ORIENTED_EDGE('',*,*,#1079,.T.);
#1096=ORIENTED_EDGE('',*,*,#153,.T.);
#1097=ORIENTED_EDGE('',*,*,#1022,.F.);
#1098=DIRECTION('',(0.,0.,-1.));
#1099=VECTOR('',#1098,1.);
#1100=CARTESIAN_POINT('',(-0.499999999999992,79.7,37.));
#1101=LINE('',#1100,#1099);
#1102=EDGE_CURVE('E397',#1078,#1021,#1101,.T.);
#1103=ORIENTED_EDGE('',*,*,#1102,.F.);
#1104=EDGE_LOOP('',(#1095,#1096,#1097,#1103));
#1105=FACE_BOUND('',#1104,.T.);
#1106=ADVANCED_FACE('F880',(#1105),#1094,.F.);
#1107=CARTESIAN_POINT('',(-0.499999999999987,0.,0.));
#1108=DIRECTION('',(-1.,0.,0.));
#1109=DIRECTION('',(0.,0.,1.));
#1110=AXIS2_PLACEMENT_3D('',#1107,#1108,#1109);
#1111=PLANE('',#1110);
#1112=ORIENTED_EDGE('',*,*,#1037,.T.);
#1113=ORIENTED_EDGE('',*,*,#1061,.T.);
#1114=ORIENTED_EDGE('',*,*,#1085,.T.);
#1115=ORIENTED_EDGE('',*,*,#1102,.T.);
#1116=EDGE_LOOP('',(#1112,#1113,#1114,#1115));
#1117=FACE_BOUND('',#1116,.T.);
#1118=ADVANCED_FACE('F876',(#1117),#1111,.T.);
#1119=CARTESIAN_POINT('',(-13.2262060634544,85.,35.5));
#1120=DIRECTION('',(0.,0.,1.));
#1121=DIRECTION('',(1.,0.,0.));
#1122=AXIS2_PLACEMENT_3D('',#1119,#1120,#1121);
#1123=PLANE('',#1122);
#1124=CARTESIAN_POINT('',(52.675,23.6,35.5));
#1125=DIRECTION('',(0.,0.,-1.));
#1126=DIRECTION('',(-1.,0.,0.));
#1127=AXIS2_PLACEMENT_3D('',#1124,#1125,#1126);
#1128=CIRCLE('',#1127,1.5);
#1129=CARTESIAN_POINT('',(51.175,23.6,35.5));
#1130=VERTEX_POINT('',#1129);
#1131=EDGE_CURVE('E691',#1130,#1130,#1128,.T.);
#1132=ORIENTED_EDGE('',*,*,#1131,.F.);
#1133=EDGE_LOOP('',(#1132));
#1134=FACE_BOUND('',#1133,.T.);
#1135=CARTESIAN_POINT('',(3.67500000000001,23.6,35.5));
#1136=DIRECTION('',(0.,0.,-1.));
#1137=DIRECTION('',(-1.,0.,0.));
#1138=AXIS2_PLACEMENT_3D('',#1135,#1136,#1137);
#1139=CIRCLE('',#1138,1.5);
#1140=CARTESIAN_POINT('',(2.17500000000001,23.6,35.5));
#1141=VERTEX_POINT('',#1140);
#1142=EDGE_CURVE('E695',#1141,#1141,#1139,.T.);
#1143=ORIENTED_EDGE('',*,*,#1142,.F.);
#1144=EDGE_LOOP('',(#1143));
#1145=FACE_BOUND('',#1144,.T.);
#1146=ORIENTED_EDGE('',*,*,#71,.F.);
#1147=EDGE_LOOP('',(#1146));
#1148=FACE_BOUND('',#1147,.T.);
#1149=CARTESIAN_POINT('',(52.675,81.6,35.5));
#1150=DIRECTION('',(0.,0.,-1.));
#1151=DIRECTION('',(-1.,0.,0.));
#1152=AXIS2_PLACEMENT_3D('',#1149,#1150,#1151);
#1153=CIRCLE('',#1152,1.5);
#1154=CARTESIAN_POINT('',(51.175,81.6,35.5));
#1155=VERTEX_POINT('',#1154);
#1156=EDGE_CURVE('E684',#1155,#1155,#1153,.T.);
#1157=ORIENTED_EDGE('',*,*,#1156,.F.);
#1158=EDGE_LOOP('',(#1157));
#1159=FACE_BOUND('',#1158,.T.);
#1160=ORIENTED_EDGE('',*,*,#54,.F.);
#1161=ORIENTED_EDGE('',*,*,#430,.F.);
#1162=ORIENTED_EDGE('',*,*,#262,.T.);
#1163=ORIENTED_EDGE('',*,*,#123,.F.);
#1164=EDGE_LOOP('',(#1160,#1161,#1162,#1163));
#1165=FACE_BOUND('',#1164,.T.);
#1166=ADVANCED_FACE('F874',(#1134,#1145,#1148,#1159,#1165),#1123,.F.);
#1167=CARTESIAN_POINT('',(0.,15.3340933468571,-52.6027959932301));
#1168=DIRECTION('',(0.,-1.,0.));
#1169=DIRECTION('',(0.,0.,-1.));
#1170=AXIS2_PLACEMENT_3D('',#1167,#1168,#1169);
#1171=PLANE('',#1170);
#1172=ORIENTED_EDGE('',*,*,#238,.T.);
#1173=ORIENTED_EDGE('',*,*,#193,.T.);
#1174=ORIENTED_EDGE('',*,*,#540,.F.);
#1175=ORIENTED_EDGE('',*,*,#108,.F.);
#1176=EDGE_LOOP('',(#1172,#1173,#1174,#1175));
#1177=FACE_BOUND('',#1176,.T.);
#1178=ADVANCED_FACE('F778',(#1177),#1171,.T.);
#1179=CARTESIAN_POINT('',(0.,0.,50.5));
#1180=DIRECTION('',(0.,0.,1.));
#1181=DIRECTION('',(1.,0.,0.));
#1182=AXIS2_PLACEMENT_3D('',#1179,#1180,#1181);
#1183=PLANE('',#1182);
#1184=EDGE_CURVE('E639',#865,#797,#539,.T.);
#1185=ORIENTED_EDGE('',*,*,#1184,.T.);
#1186=ORIENTED_EDGE('',*,*,#800,.T.);
#1187=ORIENTED_EDGE('',*,*,#917,.T.);
#1188=ORIENTED_EDGE('',*,*,#874,.F.);
#1189=EDGE_LOOP('',(#1185,#1186,#1187,#1188));
#1190=FACE_BOUND('',#1189,.T.);
#1191=ADVANCED_FACE('F609',(#1190),#1183,.T.);
#1192=ORIENTED_EDGE('',*,*,#843,.T.);
#1193=ORIENTED_EDGE('',*,*,#808,.T.);
#1194=ORIENTED_EDGE('',*,*,#1184,.F.);
#1195=ORIENTED_EDGE('',*,*,#866,.F.);
#1196=EDGE_LOOP('',(#1192,#1193,#1194,#1195));
#1197=FACE_BOUND('',#1196,.T.);
#1198=ADVANCED_FACE('F733',(#1197),#1171,.T.);
#1199=ORIENTED_EDGE('',*,*,#698,.T.);
#1200=ORIENTED_EDGE('',*,*,#664,.T.);
#1201=ORIENTED_EDGE('',*,*,#568,.F.);
#1202=ORIENTED_EDGE('',*,*,#719,.F.);
#1203=EDGE_LOOP('',(#1199,#1200,#1201,#1202));
#1204=FACE_BOUND('',#1203,.T.);
#1205=ADVANCED_FACE('F637',(#1204),#1171,.T.);
#1206=ORIENTED_EDGE('',*,*,#490,.F.);
#1207=ORIENTED_EDGE('',*,*,#466,.T.);
#1208=ORIENTED_EDGE('',*,*,#447,.T.);
#1209=ORIENTED_EDGE('',*,*,#585,.F.);
#1210=EDGE_LOOP('',(#1206,#1207,#1208,#1209));
#1211=FACE_BOUND('',#1210,.T.);
#1212=ADVANCED_FACE('F868',(#1211),#1171,.T.);
#1213=CARTESIAN_POINT('',(52.675,81.6,55.5));
#1214=DIRECTION('',(0.,0.,-1.));
#1215=DIRECTION('',(-1.,0.,0.));
#1216=AXIS2_PLACEMENT_3D('',#1213,#1214,#1215);
#1217=CYLINDRICAL_SURFACE('',#1216,1.5);
#1218=ORIENTED_EDGE('',*,*,#1156,.T.);
#1219=EDGE_LOOP('',(#1218));
#1220=FACE_BOUND('',#1219,.T.);
#1221=ORIENTED_EDGE('',*,*,#596,.F.);
#1222=EDGE_LOOP('',(#1221));
#1223=FACE_BOUND('',#1222,.T.);
#1224=ADVANCED_FACE('F862',(#1220,#1223),#1217,.F.);
#1225=CARTESIAN_POINT('',(3.67500000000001,23.6,55.5));
#1226=DIRECTION('',(0.,0.,-1.));
#1227=DIRECTION('',(-1.,0.,0.));
#1228=AXIS2_PLACEMENT_3D('',#1225,#1226,#1227);
#1229=CYLINDRICAL_SURFACE('',#1228,1.5);
#1230=ORIENTED_EDGE('',*,*,#1142,.T.);
#1231=EDGE_LOOP('',(#1230));
#1232=FACE_BOUND('',#1231,.T.);
#1233=ORIENTED_EDGE('',*,*,#616,.F.);
#1234=EDGE_LOOP('',(#1233));
#1235=FACE_BOUND('',#1234,.T.);
#1236=ADVANCED_FACE('F854',(#1232,#1235),#1229,.F.);
#1237=CARTESIAN_POINT('',(52.675,23.6,55.5));
#1238=DIRECTION('',(0.,0.,-1.));
#1239=DIRECTION('',(-1.,0.,0.));
#1240=AXIS2_PLACEMENT_3D('',#1237,#1238,#1239);
#1241=CYLINDRICAL_SURFACE('',#1240,1.5);
#1242=ORIENTED_EDGE('',*,*,#1131,.T.);
#1243=EDGE_LOOP('',(#1242));
#1244=FACE_BOUND('',#1243,.T.);
#1245=ORIENTED_EDGE('',*,*,#529,.F.);
#1246=EDGE_LOOP('',(#1245));
#1247=FACE_BOUND('',#1246,.T.);
#1248=ADVANCED_FACE('F852',(#1244,#1247),#1241,.F.);
#1249=CARTESIAN_POINT('',(-13.2086276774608,80.,50.5));
#1250=DIRECTION('',(0.,-1.,0.));
#1251=DIRECTION('',(0.,0.,-1.));
#1252=AXIS2_PLACEMENT_3D('',#1249,#1250,#1251);
#1253=PLANE('',#1252);
#1254=ORIENTED_EDGE('',*,*,#547,.F.);
#1255=ORIENTED_EDGE('',*,*,#177,.T.);
#1256=ORIENTED_EDGE('',*,*,#625,.F.);
#1257=ORIENTED_EDGE('',*,*,#400,.T.);
#1258=ORIENTED_EDGE('',*,*,#339,.T.);
#1259=ORIENTED_EDGE('',*,*,#377,.F.);
#1260=EDGE_LOOP('',(#1254,#1255,#1256,#1257,#1258,#1259));
#1261=FACE_BOUND('',#1260,.T.);
#1262=ADVANCED_FACE('F320',(#1261),#1253,.F.);
#1263=CLOSED_SHELL('',(#58,#86,#163,#227,#249,#317,#357,#388,#419,#457,#477,#516,#603,#652,#689,
#709,#755,#786,#839,#854,#900,#923,#940,#952,#969,#981,#998,#1010,#1041,#1065,#1089,#1106,#1118,
#1166,#1178,#1191,#1198,#1205,#1212,#1224,#1236,#1248,#1262));
#1264=MANIFOLD_SOLID_BREP('B2',#1263);
#1265=ADVANCED_BREP_SHAPE_REPRESENTATION('',(#18,#1264),#14);
#1266=SHAPE_DEFINITION_REPRESENTATION(#9,#1265);
ENDSEC;
END-ISO-10303-21;
